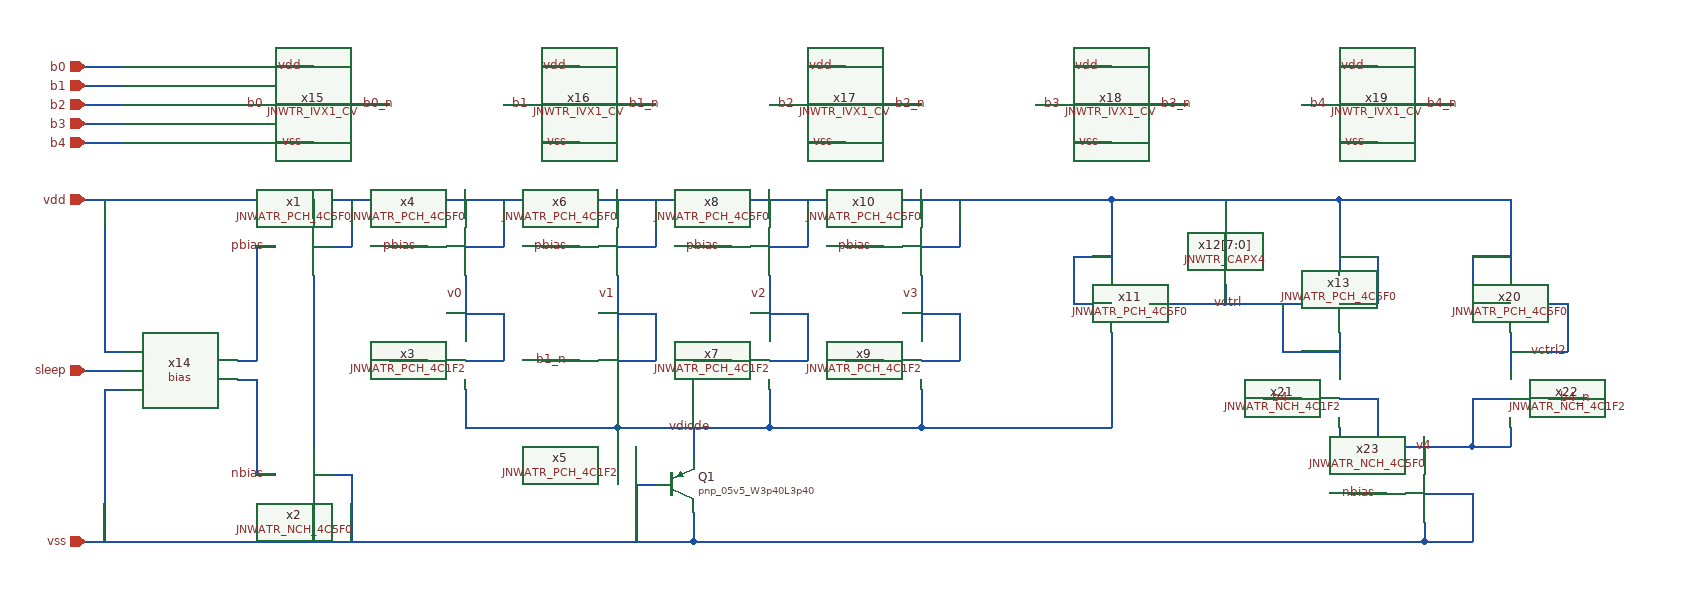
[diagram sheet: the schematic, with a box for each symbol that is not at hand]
v {xschem version=3.4.6 file_version=1.2}
G {}
K {}
V {}
S {}
E {}
N 640 500 640 520 {lab=vdd}
N 1040 740 1040 770 {lab=vdiode}
N 720 550 760 550 {lab=pbias}
N 800 500 800 520 {lab=vdd}
N 800 580 800 640 {lab=v0}
N 800 700 800 740 {lab=vdiode}
N 720 670 760 670 {lab=b0_n}
N 800 550 840 550 {lab=vdd}
N 840 500 840 550 {lab=vdd}
N 800 670 840 670 {lab=v0}
N 840 620 840 670 {lab=v0}
N 800 620 840 620 {lab=v0}
N 800 740 960 740 {lab=vdiode}
N 880 550 920 550 {lab=pbias}
N 960 500 960 520 {lab=vdd}
N 960 580 960 640 {lab=v1}
N 960 700 960 740 {lab=vdiode}
N 880 670 920 670 {lab=b1_n}
N 960 550 1000 550 {lab=vdd}
N 1000 500 1000 550 {lab=vdd}
N 960 670 1000 670 {lab=v1}
N 1000 620 1000 670 {lab=v1}
N 960 620 1000 620 {lab=v1}
N 960 740 1120 740 {lab=vdiode}
N 1040 550 1080 550 {lab=pbias}
N 1120 500 1120 520 {lab=vdd}
N 1120 580 1120 640 {lab=v2}
N 1120 700 1120 740 {lab=vdiode}
N 1040 670 1080 670 {lab=b2_n}
N 1120 550 1160 550 {lab=vdd}
N 1160 500 1160 550 {lab=vdd}
N 1120 670 1160 670 {lab=v2}
N 1160 620 1160 670 {lab=v2}
N 1120 620 1160 620 {lab=v2}
N 1120 740 1280 740 {lab=vdiode}
N 1200 550 1240 550 {lab=pbias}
N 1280 500 1280 520 {lab=vdd}
N 1280 580 1280 640 {lab=v3}
N 1280 700 1280 740 {lab=vdiode}
N 1200 670 1240 670 {lab=b3_n}
N 1280 550 1320 550 {lab=vdd}
N 1320 500 1320 550 {lab=vdd}
N 1280 670 1320 670 {lab=v3}
N 1320 620 1320 670 {lab=v3}
N 1280 620 1320 620 {lab=v3}
N 400 500 1480 500 {lab=vdd}
N 1040 830 1040 860 {lab=vss}
N 980 800 1000 800 {lab=vss}
N 980 800 980 860 {lab=vss}
N 400 860 1040 860 {lab=vss}
N 560 400 600 400 {lab=b0}
N 400 380 440 380 {lab=b1}
N 400 400 440 400 {lab=b2}
N 400 420 440 420 {lab=b3}
N 400 440 440 440 {lab=b4}
N 600 360 640 360 {lab=vdd}
N 600 440 640 440 {lab=vss}
N 680 400 720 400 {lab=b0_n}
N 840 400 880 400 {lab=b1}
N 880 360 920 360 {lab=vdd}
N 880 440 920 440 {lab=vss}
N 960 400 1000 400 {lab=b1_n}
N 1120 400 1160 400 {lab=b2}
N 1160 360 1200 360 {lab=vdd}
N 1160 440 1200 440 {lab=vss}
N 1240 400 1280 400 {lab=b2_n}
N 1400 400 1440 400 {lab=b3}
N 1440 360 1480 360 {lab=vdd}
N 1440 440 1480 440 {lab=vss}
N 1520 400 1560 400 {lab=b3_n}
N 1680 400 1720 400 {lab=b4}
N 1720 360 1760 360 {lab=vdd}
N 1720 440 1760 440 {lab=vss}
N 1800 400 1840 400 {lab=b4_n}
N 400 360 440 360 {lab=b0}
N 640 550 680 550 {lab=vdd}
N 680 500 680 550 {lab=vdd}
N 640 580 640 760 {lab=#net1}
N 640 790 680 790 {lab=vss}
N 680 790 680 860 {lab=vss}
N 640 820 640 860 {lab=vss}
N 400 680 440 680 {lab=sleep}
N 420 500 420 660 {lab=vdd}
N 420 700 420 860 {lab=vss}
N 580 690 580 790 {lab=nbias}
N 580 790 600 790 {lab=nbias}
N 580 550 580 670 {lab=pbias}
N 580 550 600 550 {lab=pbias}
N 560 690 580 690 {lab=nbias}
N 560 670 580 670 {lab=pbias}
N 420 700 440 700 {lab=vss}
N 420 660 440 660 {lab=vdd}
N 1520 610 1680 610 {lab=vctrl}
N 1480 500 1480 580 {lab=vdd}
N 1280 740 1480 740 {lab=vdiode}
N 1040 860 1810 860 {lab=vss}
N 1600 590 1600 610 {lab=vctrl}
N 1600 500 1600 520 {lab=vdd}
N 1480 500 1720 500 {lab=vdd}
N 1720 500 1720 580 {lab=vdd}
N 1720 610 1760 610 {lab=vdd}
N 1760 560 1760 610 {lab=vdd}
N 1720 560 1760 560 {lab=vdd}
N 1660 610 1660 660 {lab=vctrl}
N 1660 660 1720 660 {lab=vctrl}
N 1720 640 1720 680 {lab=vctrl}
N 1940 610 1960 610 {lab=vctrl2}
N 1900 500 1900 580 {lab=vdd}
N 1860 610 1900 610 {lab=vdd}
N 1860 560 1860 610 {lab=vdd}
N 1960 610 1960 660 {lab=vctrl2}
N 1900 660 1960 660 {lab=vctrl2}
N 1900 640 1900 680 {lab=vctrl2}
N 1720 500 1900 500 {lab=vdd}
N 1860 560 1900 560 {lab=vdd}
N 1480 640 1480 740 {lab=vdiode}
N 1860 710 1900 710 {lab=v4}
N 1860 710 1860 760 {lab=v4}
N 1860 760 1900 760 {lab=v4}
N 1720 710 1760 710 {lab=v4}
N 1760 710 1760 760 {lab=v4}
N 1720 760 1760 760 {lab=v4}
N 1720 740 1720 760 {lab=v4}
N 1900 740 1900 760 {lab=v4}
N 1640 710 1680 710 {lab=b4}
N 1940 710 1980 710 {lab=b4_n}
N 1760 760 1860 760 {lab=v4}
N 1810 760 1810 780 {lab=v4}
N 1860 810 1860 860 {lab=vss}
N 1440 610 1480 610 {lab=vdd}
N 1440 560 1440 610 {lab=vdd}
N 1440 560 1480 560 {lab=vdd}
N 1810 840 1810 860 {lab=vss}
N 1810 810 1860 810 {lab=vss}
N 1810 860 1860 860 {lab=vss}
N 1730 810 1770 810 {lab=nbias}
C {JNW_ATR_SKY130A/JNWATR_PCH_4C5F0.sym} 600 550 0 0 {name=x1 }
C {JNW_ATR_SKY130A/JNWATR_PCH_4C5F0.sym} 760 550 0 0 {name=x4 }
C {JNW_ATR_SKY130A/JNWATR_PCH_4C5F0.sym} 920 550 0 0 {name=x6 }
C {JNW_ATR_SKY130A/JNWATR_PCH_4C5F0.sym} 1080 550 0 0 {name=x8 }
C {JNW_ATR_SKY130A/JNWATR_PCH_4C5F0.sym} 1240 550 0 0 {name=x10 }
C {devices/lab_wire.sym} 1230 670 0 0 {name=p3 sig_type=std_logic lab=b3_n
}
C {devices/lab_wire.sym} 1070 670 0 0 {name=p4 sig_type=std_logic lab=b2_n
}
C {devices/lab_wire.sym} 910 670 0 0 {name=p5 sig_type=std_logic lab=b1_n
}
C {devices/lab_wire.sym} 750 670 0 0 {name=p6 sig_type=std_logic lab=b0_n
}
C {devices/ipin.sym} 400 500 0 0 {name=p14 lab=vdd}
C {sky130_fd_pr/pnp_05v5.sym} 1020 800 0 0 {name=Q1
model=pnp_05v5_W3p40L3p40
m=1
spiceprefix=X
}
C {devices/ipin.sym} 400 860 0 0 {name=p15 lab=vss}
C {devices/ipin.sym} 400 380 0 0 {name=p17 lab=b1}
C {devices/ipin.sym} 400 400 0 0 {name=p18 lab=b2}
C {devices/ipin.sym} 400 420 0 0 {name=p19 lab=b3}
C {devices/ipin.sym} 400 440 0 0 {name=p20 lab=b4}
C {JNW_TR_SKY130A/JNWTR_IVX1_CV.sym} 600 400 0 0 {name=x15 }
C {devices/lab_wire.sym} 630 440 2 1 {name=p23 sig_type=std_logic lab=vss}
C {devices/lab_wire.sym} 630 360 0 0 {name=p24 sig_type=std_logic lab=vdd}
C {JNW_TR_SKY130A/JNWTR_IVX1_CV.sym} 880 400 0 0 {name=x16 }
C {devices/lab_wire.sym} 910 440 2 1 {name=p26 sig_type=std_logic lab=vss}
C {devices/lab_wire.sym} 910 360 0 0 {name=p27 sig_type=std_logic lab=vdd}
C {JNW_TR_SKY130A/JNWTR_IVX1_CV.sym} 1160 400 0 0 {name=x17 }
C {devices/lab_wire.sym} 1190 440 2 1 {name=p30 sig_type=std_logic lab=vss}
C {devices/lab_wire.sym} 1190 360 0 0 {name=p31 sig_type=std_logic lab=vdd}
C {JNW_TR_SKY130A/JNWTR_IVX1_CV.sym} 1440 400 0 0 {name=x18 }
C {devices/lab_wire.sym} 1470 440 2 1 {name=p34 sig_type=std_logic lab=vss}
C {devices/lab_wire.sym} 1470 360 0 0 {name=p35 sig_type=std_logic lab=vdd}
C {JNW_TR_SKY130A/JNWTR_IVX1_CV.sym} 1720 400 0 0 {name=x19 }
C {devices/lab_wire.sym} 1750 440 2 1 {name=p38 sig_type=std_logic lab=vss}
C {devices/lab_wire.sym} 1750 360 0 0 {name=p39 sig_type=std_logic lab=vdd}
C {devices/lab_wire.sym} 590 400 0 0 {name=p16 sig_type=std_logic lab=b0}
C {devices/lab_wire.sym} 1430 400 0 0 {name=p25 sig_type=std_logic lab=b3}
C {devices/lab_wire.sym} 870 400 0 0 {name=p28 sig_type=std_logic lab=b1}
C {devices/lab_wire.sym} 1710 400 0 0 {name=p29 sig_type=std_logic lab=b4}
C {devices/lab_wire.sym} 1150 400 0 0 {name=p32 sig_type=std_logic lab=b2}
C {devices/ipin.sym} 400 360 0 0 {name=p7 lab=b0}
C {devices/lab_wire.sym} 1530 400 0 1 {name=p36 sig_type=std_logic lab=b3_n}
C {devices/lab_wire.sym} 690 400 0 1 {name=p37 sig_type=std_logic lab=b0_n}
C {devices/lab_wire.sym} 970 400 0 1 {name=p40 sig_type=std_logic lab=b1_n}
C {devices/lab_wire.sym} 1810 400 0 1 {name=p41 sig_type=std_logic lab=b4_n}
C {devices/lab_wire.sym} 1250 400 0 1 {name=p45 sig_type=std_logic lab=b2_n}
C {devices/lab_wire.sym} 910 550 0 0 {name=p9 sig_type=std_logic lab=pbias
}
C {devices/lab_wire.sym} 1070 550 0 0 {name=p8 sig_type=std_logic lab=pbias
}
C {devices/lab_wire.sym} 1230 550 0 0 {name=p10 sig_type=std_logic lab=pbias
}
C {JNW_ATR_SKY130A/JNWATR_NCH_4C5F0.sym} 600 790 0 0 {name=x2}
C {devices/lab_wire.sym} 750 550 0 0 {name=p12 sig_type=std_logic lab=pbias
}
C {LELO_TORD_SKY130A/bias.sym} 500 680 0 0 {name=x14}
C {devices/ipin.sym} 400 680 0 0 {name=p33 lab=sleep}
C {devices/lab_wire.sym} 590 550 0 0 {name=p13 sig_type=std_logic lab=pbias
}
C {devices/lab_wire.sym} 590 790 2 1 {name=p21 sig_type=std_logic lab=nbias
}
C {devices/lab_wire.sym} 1060 740 0 0 {name=p22 sig_type=std_logic lab=vdiode
}
C {JNW_ATR_SKY130A/JNWATR_PCH_4C5F0.sym} 1520 610 0 1 {name=x11 }
C {JNW_ATR_SKY130A/JNWATR_PCH_4C1F2.sym} 760 670 0 0 {name=x3 }
C {JNW_ATR_SKY130A/JNWATR_PCH_4C1F2.sym} 920 670 0 0 {name=x5 }
C {JNW_ATR_SKY130A/JNWATR_PCH_4C1F2.sym} 1080 670 0 0 {name=x7 }
C {JNW_ATR_SKY130A/JNWATR_PCH_4C1F2.sym} 1240 670 0 0 {name=x9 }
C {JNW_TR_SKY130A/JNWTR_CAPX4.sym} 1600 580 0 0 {name=x12[7:0]}
C {JNW_ATR_SKY130A/JNWATR_PCH_4C5F0.sym} 1680 610 0 0 {name=x13 }
C {JNW_ATR_SKY130A/JNWATR_PCH_4C5F0.sym} 1940 610 0 1 {name=x20 }
C {JNW_ATR_SKY130A/JNWATR_NCH_4C1F2.sym} 1680 710 0 0 {name=x21 }
C {JNW_ATR_SKY130A/JNWATR_NCH_4C1F2.sym} 1940 710 0 1 {name=x22 }
C {devices/lab_wire.sym} 1950 710 0 1 {name=p1 sig_type=std_logic lab=b4_n}
C {devices/lab_wire.sym} 1670 710 0 0 {name=p2 sig_type=std_logic lab=b4}
C {JNW_ATR_SKY130A/JNWATR_NCH_4C5F0.sym} 1770 810 0 0 {name=x23 }
C {devices/lab_wire.sym} 1760 810 2 1 {name=p11 sig_type=std_logic lab=nbias
}
C {devices/lab_wire.sym} 1620 610 2 1 {name=p42 sig_type=std_logic lab=vctrl}
C {devices/lab_wire.sym} 1920 660 2 0 {name=p43 sig_type=std_logic lab=vctrl2}
C {devices/lab_wire.sym} 1820 760 0 0 {name=p44 sig_type=std_logic lab=v4}
C {devices/lab_wire.sym} 1280 600 2 1 {name=p46 sig_type=std_logic lab=v3}
C {devices/lab_wire.sym} 1120 600 2 1 {name=p47 sig_type=std_logic lab=v2}
C {devices/lab_wire.sym} 960 600 2 1 {name=p48 sig_type=std_logic lab=v1}
C {devices/lab_wire.sym} 800 600 2 1 {name=p49 sig_type=std_logic lab=v0
}
